VERSION 5.8 ;
BUSBITCHARS "[]" ;
DIVIDERCHAR "/" ;

PROPERTYDEFINITIONS
  MACRO SDLglobal STRING ;
  MACRO SDLpower STRING ;
  MACRO SDLground STRING ;
END PROPERTYDEFINITIONS

VIA M1M2_C_0
  VIARULE M1M2_C ;
  CUTSIZE 0.15 0.15 ;
  LAYERS met1 via met2 ;
  CUTSPACING 0.17 0.17 ;
  ENCLOSURE 0.085 0.085 0.085 0.085 ;
  ROWCOL 1 1 ;
END M1M2_C_0

VIA M1M2_C_1
  VIARULE M1M2_C ;
  CUTSIZE 0.15 0.15 ;
  LAYERS met1 via met2 ;
  CUTSPACING 0.17 0.17 ;
  ENCLOSURE 0.085 0.085 0.085 0.085 ;
  ROWCOL 3 1 ;
END M1M2_C_1

VIA M1M2_C_2
  VIARULE M1M2_C ;
  CUTSIZE 0.15 0.15 ;
  LAYERS met1 via met2 ;
  CUTSPACING 0.17 0.17 ;
  ENCLOSURE 0.085 0.085 0.085 0.085 ;
  ROWCOL 1 2 ;
END M1M2_C_2

VIA L1M1_C_3
  VIARULE L1M1_C ;
  CUTSIZE 0.17 0.17 ;
  LAYERS li1 mcon met1 ;
  CUTSPACING 0.19 0.19 ;
  ENCLOSURE 0 0 0.06 0.06 ;
  ROWCOL 1 1 ;
END L1M1_C_3

VIA L1M1_C_4
  VIARULE L1M1_C ;
  CUTSIZE 0.17 0.17 ;
  LAYERS li1 mcon met1 ;
  CUTSPACING 0.19 0.19 ;
  ENCLOSURE 0 0 0.06 0.06 ;
  ROWCOL 5 1 ;
END L1M1_C_4

VIA L1M1_C_5
  VIARULE L1M1_C ;
  CUTSIZE 0.17 0.17 ;
  LAYERS li1 mcon met1 ;
  CUTSPACING 0.19 0.19 ;
  ENCLOSURE 0 0 0.06 0.06 ;
  ROWCOL 12 1 ;
END L1M1_C_5

VIA L1M1_C_6
  VIARULE L1M1_C ;
  CUTSIZE 0.17 0.17 ;
  LAYERS li1 mcon met1 ;
  CUTSPACING 0.19 0.19 ;
  ENCLOSURE 0 0 0.06 0.06 ;
  ROWCOL 1 2 ;
END L1M1_C_6

VIA PYL1_C_7
  VIARULE PYL1_C ;
  CUTSIZE 0.17 0.17 ;
  LAYERS poly licon1 li1 ;
  CUTSPACING 0.17 0.17 ;
  ENCLOSURE 0.08 0.08 0.08 0.08 ;
  ROWCOL 1 1 ;
END PYL1_C_7

VIA PYL1_C_8
  VIARULE PYL1_C ;
  CUTSIZE 0.17 0.17 ;
  LAYERS poly licon1 li1 ;
  CUTSPACING 0.17 0.17 ;
  ENCLOSURE 0.08 0.08 0.08 0.08 ;
  ROWCOL 8 1 ;
END PYL1_C_8

VIA PYL1_C_9
  VIARULE PYL1_C ;
  CUTSIZE 0.17 0.17 ;
  LAYERS poly licon1 li1 ;
  CUTSPACING 0.17 0.17 ;
  ENCLOSURE 0.08 0.08 0.08 0.08 ;
  ROWCOL 2 1 ;
END PYL1_C_9

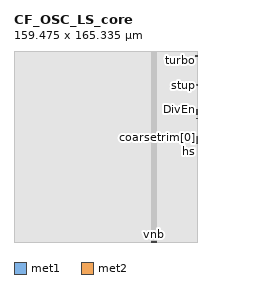
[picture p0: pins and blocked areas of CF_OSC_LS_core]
MACRO CF_OSC_LS_core
  ORIGIN 0 0 ;
  FOREIGN CF_OSC_LS_core 0 0 ;
  SIZE 159.475 BY 165.335 ;
  PIN trim100k[3]
    DIRECTION INPUT ;
    USE SIGNAL ;
    PORT
      LAYER met1 ;
        RECT 158.505 87.165 159.475 87.395 ;
    END
  END trim100k[3]
  PIN trim100k[2]
    DIRECTION INPUT ;
    USE SIGNAL ;
    PORT
      LAYER met1 ;
        RECT 158.505 86.685 159.475 86.915 ;
    END
  END trim100k[2]
  PIN trim100k[1]
    DIRECTION INPUT ;
    USE SIGNAL ;
    PORT
      LAYER met1 ;
        RECT 158.505 86.205 159.475 86.435 ;
    END
  END trim100k[1]
  PIN trim100k[0]
    DIRECTION INPUT ;
    USE SIGNAL ;
    PORT
      LAYER met1 ;
        RECT 158.505 85.725 159.475 85.955 ;
    END
  END trim100k[0]
  PIN trim1k[3]
    DIRECTION INPUT ;
    USE SIGNAL ;
    PORT
      LAYER met1 ;
        RECT 158.505 90.09 159.475 90.23 ;
    END
  END trim1k[3]
  PIN trim1k[2]
    DIRECTION INPUT ;
    USE SIGNAL ;
    PORT
      LAYER met1 ;
        RECT 158.505 89.61 159.475 89.75 ;
    END
  END trim1k[2]
  PIN trim1k[1]
    DIRECTION INPUT ;
    USE SIGNAL ;
    PORT
      LAYER met1 ;
        RECT 158.505 89.13 159.475 89.27 ;
    END
  END trim1k[1]
  PIN trim1k[0]
    DIRECTION INPUT ;
    USE SIGNAL ;
    PORT
      LAYER met1 ;
        RECT 158.505 88.65 159.475 88.79 ;
    END
  END trim1k[0]
  PIN coarsetrim[2]
    DIRECTION INPUT ;
    USE SIGNAL ;
    PORT
      LAYER met1 ;
        RECT 158.505 88.17 159.475 88.31 ;
    END
  END coarsetrim[2]
  PIN coarsetrim[1]
    DIRECTION INPUT ;
    USE SIGNAL ;
    PORT
      LAYER met1 ;
        RECT 158.505 90.635 159.47 90.775 ;
    END
  END coarsetrim[1]
  PIN coarsetrim[0]
    DIRECTION INPUT ;
    USE SIGNAL ;
    PORT
      LAYER met1 ;
        RECT 158.505 91.115 159.47 91.255 ;
    END
  END coarsetrim[0]
  PIN vpwr
    DIRECTION INOUT ;
    USE SIGNAL ;
    PORT
      LAYER met2 ;
        RECT 123.03 0 123.99 0.4 ;
    END
  END vpwr
  PIN vpb
    DIRECTION INOUT ;
    USE SIGNAL ;
    PORT
      LAYER met2 ;
        RECT 120.785 0 121.425 0.4 ;
    END
  END vpb
  PIN vnb
    DIRECTION INOUT ;
    USE SIGNAL ;
    PORT
      LAYER met2 ;
        RECT 121.915 0 122.555 0.4 ;
    END
  END vnb
  PIN vgnd
    DIRECTION INOUT ;
    USE SIGNAL ;
    PORT
      LAYER met2 ;
        RECT 119.535 0 120.495 0.4 ;
    END
  END vgnd
  PIN clkout_div3
    DIRECTION OUTPUT ;
    USE SIGNAL ;
    PORT
      LAYER met1 ;
        RECT 158.505 111.325 159.475 111.585 ;
    END
  END clkout_div3
  PIN clkout2
    DIRECTION OUTPUT ;
    USE SIGNAL ;
    PORT
      LAYER met1 ;
        RECT 158.505 107.17 159.475 107.43 ;
    END
  END clkout2
  PIN clkout1
    DIRECTION OUTPUT ;
    USE SIGNAL ;
    PORT
      LAYER met1 ;
        RECT 158.505 113.345 159.475 113.485 ;
    END
  END clkout1
  PIN turbo
    DIRECTION INPUT ;
    USE SIGNAL ;
    PORT
      LAYER met1 ;
        RECT 157.975 161.755 159.475 161.985 ;
    END
  END turbo
  PIN stup
    DIRECTION INPUT ;
    USE SIGNAL ;
    PORT
      LAYER met1 ;
        RECT 157.895 136.25 159.475 136.48 ;
    END
  END stup
  PIN satbiasb
    DIRECTION INPUT ;
    USE SIGNAL ;
    PORT
      LAYER met1 ;
        RECT 158.505 87.69 159.475 87.83 ;
    END
  END satbiasb
  PIN pdb
    DIRECTION INPUT ;
    USE SIGNAL ;
    PORT
      LAYER met1 ;
        RECT 157.895 136.965 159.475 137.225 ;
    END
  END pdb
  PIN pd_mode
    DIRECTION INPUT ;
    USE SIGNAL ;
    PORT
      LAYER met1 ;
        RECT 158.505 91.6 159.475 91.74 ;
    END
  END pd_mode
  PIN hs
    DIRECTION INPUT ;
    USE SIGNAL ;
    PORT
      LAYER met1 ;
        RECT 158.505 85.29 159.475 85.43 ;
    END
  END hs
  PIN En100k
    DIRECTION INPUT ;
    USE SIGNAL ;
    PORT
      LAYER met1 ;
        RECT 158.505 112.365 159.475 112.505 ;
    END
  END En100k
  PIN En1k
    DIRECTION INPUT ;
    USE SIGNAL ;
    PORT
      LAYER met1 ;
        RECT 158.505 92.085 159.475 92.225 ;
    END
  END En1k
  PIN DivEn
    DIRECTION INPUT ;
    USE SIGNAL ;
    PORT
      LAYER met1 ;
        RECT 158.505 114.82 159.475 114.96 ;
    END
  END DivEn
  OBS
    LAYER met3 ;
      RECT 73.255 0 90.59 92.425 ;
      RECT 110.215 148.765 146.78 165.335 ;
      RECT 100.1 0 149.27 87.535 ;
      RECT 0 45.05 42.66 90.34 ;
      RECT 111.42 93.215 159.475 140.38 ;
      RECT 54.955 -6.88 54.965 -6.865 ;
      RECT 48.035 0 69.62 92.425 ;
    LAYER li1 ;
      RECT 0 0 159.475 165.335 ;
    LAYER met1 ;
      RECT 0 0 157.895 165.335 ;
      RECT 157.895 0 157.975 136.25 ;
      RECT 157.895 136.48 157.975 136.965 ;
      RECT 157.895 137.225 157.975 165.335 ;
      RECT 157.975 0 158.505 136.25 ;
      RECT 157.975 136.48 158.505 136.965 ;
      RECT 157.975 137.225 158.505 161.755 ;
      RECT 157.975 161.985 158.505 165.335 ;
      RECT 158.505 0 159.47 85.29 ;
      RECT 158.505 85.43 159.47 85.725 ;
      RECT 158.505 85.955 159.47 86.205 ;
      RECT 158.505 86.435 159.47 86.685 ;
      RECT 158.505 86.915 159.47 87.165 ;
      RECT 158.505 87.395 159.47 87.69 ;
      RECT 158.505 87.83 159.47 88.17 ;
      RECT 158.505 88.31 159.47 88.65 ;
      RECT 158.505 88.79 159.47 89.13 ;
      RECT 158.505 89.27 159.47 89.61 ;
      RECT 158.505 89.75 159.47 90.09 ;
      RECT 158.505 90.23 159.47 90.635 ;
      RECT 158.505 90.775 159.47 91.115 ;
      RECT 158.505 91.255 159.47 91.6 ;
      RECT 158.505 91.74 159.47 92.085 ;
      RECT 158.505 92.225 159.47 107.17 ;
      RECT 158.505 107.43 159.47 111.325 ;
      RECT 158.505 111.585 159.47 112.365 ;
      RECT 158.505 112.505 159.47 113.345 ;
      RECT 158.505 113.485 159.47 114.82 ;
      RECT 158.505 114.96 159.47 136.25 ;
      RECT 158.505 136.48 159.47 136.965 ;
      RECT 158.505 137.225 159.47 161.755 ;
      RECT 158.505 161.985 159.47 165.335 ;
      RECT 159.47 0 159.475 85.29 ;
      RECT 159.47 85.43 159.475 85.725 ;
      RECT 159.47 85.955 159.475 86.205 ;
      RECT 159.47 86.435 159.475 86.685 ;
      RECT 159.47 86.915 159.475 87.165 ;
      RECT 159.47 87.395 159.475 87.69 ;
      RECT 159.47 87.83 159.475 88.17 ;
      RECT 159.47 88.31 159.475 88.65 ;
      RECT 159.47 88.79 159.475 89.13 ;
      RECT 159.47 89.27 159.475 89.61 ;
      RECT 159.47 89.75 159.475 90.09 ;
      RECT 159.47 90.23 159.475 91.6 ;
      RECT 159.47 91.74 159.475 92.085 ;
      RECT 159.47 92.225 159.475 107.17 ;
      RECT 159.47 107.43 159.475 111.325 ;
      RECT 159.47 111.585 159.475 112.365 ;
      RECT 159.47 112.505 159.475 113.345 ;
      RECT 159.47 113.485 159.475 114.82 ;
      RECT 159.47 114.96 159.475 136.25 ;
      RECT 159.47 136.48 159.475 136.965 ;
      RECT 159.47 137.225 159.475 161.755 ;
      RECT 159.47 161.985 159.475 165.335 ;
    LAYER met2 ;
      RECT 0 0 119.535 165.335 ;
      RECT 119.535 0.4 120.495 165.335 ;
      RECT 120.495 0 120.785 165.335 ;
      RECT 120.785 0.4 121.425 165.335 ;
      RECT 121.425 0 121.915 165.335 ;
      RECT 121.915 0.4 122.555 165.335 ;
      RECT 122.555 0 123.03 165.335 ;
      RECT 123.03 0.4 123.99 165.335 ;
      RECT 123.99 0 159.475 165.335 ;
  END
  PROPERTY SDLglobal "" ;
  PROPERTY SDLpower "vpwr" ;
  PROPERTY SDLground "vgnd" ;
END CF_OSC_LS_core

END LIBRARY
